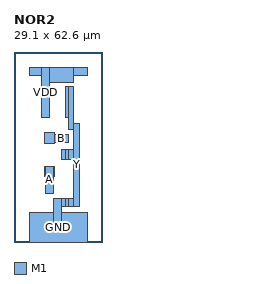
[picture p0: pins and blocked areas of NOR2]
MACRO NOR2
  CLASS CORE ;
  ORIGIN 0 0 ;
  SIZE 29.100 BY 62.600 ;
  SYMMETRY X Y ;
  SITE TR1um_site ;
  PIN A
    DIRECTION INPUT ;
    USE SIGNAL ;
    PORT
      LAYER M1 ;
        RECT 10.100 21.600 10.300 25.000 ;
      LAYER M1 ;
        RECT 10.300 16.000 12.900 25.000 ;
      LAYER M1 ;
        RECT 12.900 21.600 13.500 25.000 ;
    END
  END A
  PIN B
    DIRECTION INPUT ;
    USE SIGNAL ;
    PORT
      LAYER M1 ;
        RECT 10.100 32.600 13.500 36.000 ;
      LAYER M1 ;
        RECT 13.500 32.900 18.100 35.500 ;
    END
  END B
  PIN Y
    DIRECTION OUTPUT ;
    USE SIGNAL ;
    PORT
      LAYER M1 ;
        RECT 13.100 6.400 15.600 14.400 ;
      LAYER M1 ;
        RECT 15.600 6.400 15.700 14.400 ;
      LAYER M1 ;
        RECT 15.600 27.100 15.700 30.500 ;
      LAYER M1 ;
        RECT 15.700 11.800 17.100 14.400 ;
      LAYER M1 ;
        RECT 15.700 27.100 17.100 30.500 ;
      LAYER M1 ;
        RECT 17.100 11.800 17.900 14.400 ;
      LAYER M1 ;
        RECT 17.100 27.100 17.900 30.500 ;
      LAYER M1 ;
        RECT 17.100 41.000 17.900 51.200 ;
      LAYER M1 ;
        RECT 17.900 11.800 19.700 14.400 ;
      LAYER M1 ;
        RECT 17.900 27.100 19.700 30.500 ;
      LAYER M1 ;
        RECT 17.900 37.200 19.700 51.200 ;
      LAYER M1 ;
        RECT 19.700 11.800 21.500 39.000 ;
    END
  END Y
  PIN VDD
    DIRECTION INOUT ;
    USE POWER ;
    PORT
      LAYER M1 ;
        RECT 5.000 55.000 9.100 57.600 ;
      LAYER M1 ;
        RECT 9.100 41.000 11.700 57.600 ;
      LAYER M1 ;
        RECT 11.700 52.600 19.700 57.600 ;
      LAYER M1 ;
        RECT 19.700 55.000 24.100 57.600 ;
    END
  END VDD
  PIN GND
    DIRECTION INOUT ;
    USE GROUND ;
    PORT
      LAYER M1 ;
        RECT 5.000 0.000 24.100 9.800 ;
    END
  END GND
END NOR2
